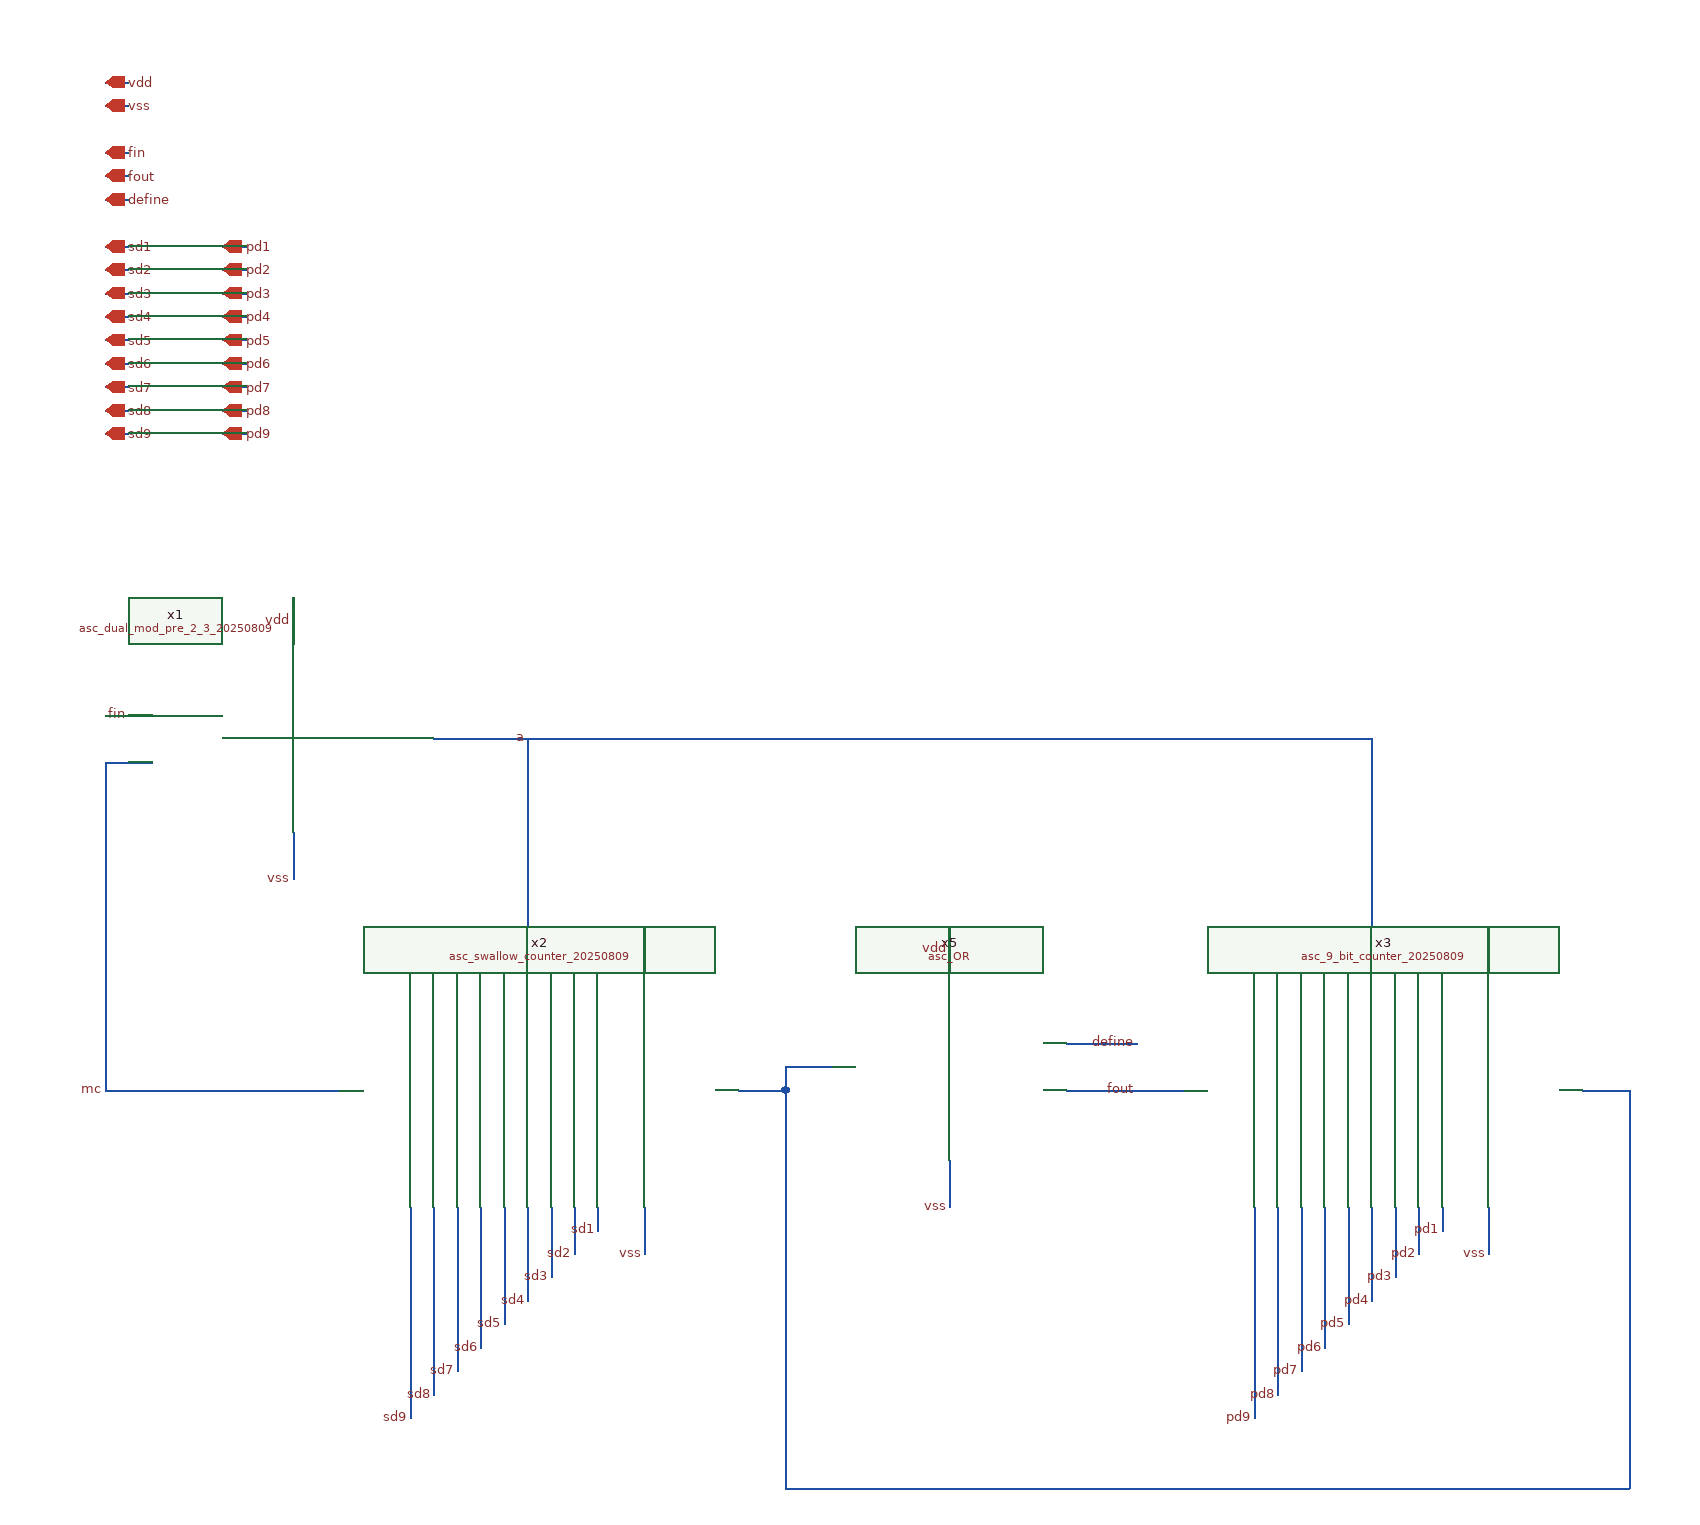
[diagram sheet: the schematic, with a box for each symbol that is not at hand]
v {xschem version=3.4.7 file_version=1.2}
G {}
K {}
V {}
S {}
E {}
N 280 -820 280 -780 {lab=vdd}
N 280 -620 280 -580 {lab=vss}
N 400 -700 540 -700 {lab=a}
N 120 -720 160 -720 {lab=fin}
N 580 -300 580 -260 {lab=vss}
N 580 -540 580 -500 {lab=vdd}
N 480 -700 480 -500 {lab=a}
N 520 -300 520 -270 {lab=sd2}
N 520 -270 520 -260 {lab=sd2}
N 500 -300 500 -260 {lab=sd3}
N 480 -300 480 -260 {lab=sd4}
N 460 -300 460 -260 {lab=sd5}
N 440 -300 440 -260 {lab=sd6}
N 420 -300 420 -260 {lab=sd7}
N 380 -300 380 -270 {lab=sd9}
N 380 -270 380 -260 {lab=sd9}
N 120 -400 320 -400 {lab=mc}
N 120 -680 120 -400 {lab=mc}
N 120 -680 160 -680 {lab=mc}
N 400 -300 400 -260 {lab=sd8}
N 380 -260 380 -160 {lab=sd9}
N 380 -160 380 -140 {lab=sd9}
N 380 -140 380 -120 {lab=sd9}
N 400 -260 400 -140 {lab=sd8}
N 420 -260 420 -160 {lab=sd7}
N 440 -260 440 -180 {lab=sd6}
N 460 -260 460 -200 {lab=sd5}
N 480 -260 480 -220 {lab=sd4}
N 500 -260 500 -240 {lab=sd3}
N 540 -300 540 -280 {lab=sd1}
N 1300 -300 1300 -260 {lab=vss}
N 1240 -300 1240 -270 {lab=pd2}
N 1240 -270 1240 -260 {lab=pd2}
N 1220 -300 1220 -260 {lab=pd3}
N 1200 -300 1200 -260 {lab=pd4}
N 1180 -300 1180 -260 {lab=pd5}
N 1160 -300 1160 -260 {lab=pd6}
N 1140 -300 1140 -260 {lab=pd7}
N 1100 -300 1100 -270 {lab=pd9}
N 1100 -270 1100 -260 {lab=pd9}
N 1120 -300 1120 -260 {lab=pd8}
N 1100 -260 1100 -160 {lab=pd9}
N 1100 -160 1100 -140 {lab=pd9}
N 1100 -140 1100 -120 {lab=pd9}
N 1120 -260 1120 -140 {lab=pd8}
N 1140 -260 1140 -160 {lab=pd7}
N 1160 -260 1160 -180 {lab=pd6}
N 1180 -260 1180 -200 {lab=pd5}
N 1200 -260 1200 -220 {lab=pd4}
N 1220 -260 1220 -240 {lab=pd3}
N 1260 -300 1260 -280 {lab=pd1b}
N 1300 -540 1300 -500 {lab=vdd}
N 700 -420 740 -420 {lab=#net1}
N 540 -700 900 -700 {lab=a}
N 1200 -700 1200 -500 {lab=a}
N 840 -540 840 -500 {lab=vdd}
N 840 -340 840 -300 {lab=vss}
N 940 -440 980 -440 {lab=define}
N 940 -400 980 -400 {lab=fout}
N 120 -1260 140 -1260 {lab=vdd}
N 120 -1240 140 -1240 {lab=vss}
N 120 -1100 140 -1100 {lab=sd2}
N 120 -1120 140 -1120 {lab=sd1}
N 120 -1080 140 -1080 {lab=sd3}
N 120 -1040 140 -1040 {lab=sd5}
N 120 -1060 140 -1060 {lab=sd4}
N 120 -1020 140 -1020 {lab=sd6}
N 120 -980 140 -980 {lab=sd8}
N 120 -1000 140 -1000 {lab=sd7}
N 120 -960 140 -960 {lab=sd9}
N 120 -1160 140 -1160 {lab=define}
N 120 -1200 140 -1200 {lab=fin}
N 120 -1180 140 -1180 {lab=fout}
N 220 -1100 240 -1100 {lab=pd2}
N 220 -1120 240 -1120 {lab=pd1}
N 220 -1080 240 -1080 {lab=pd3}
N 220 -1040 240 -1040 {lab=pd5}
N 220 -1060 240 -1060 {lab=pd4}
N 220 -1020 240 -1020 {lab=pd6}
N 220 -980 240 -980 {lab=pd8}
N 220 -1000 240 -1000 {lab=pd7}
N 220 -960 240 -960 {lab=pd9}
N 1140 -700 1200 -700 {lab=a}
N 700 -420 700 -400 {lab=#net1}
N 660 -400 700 -400 {lab=#net1}
N 980 -400 1040 -400 {lab=fout}
N 700 -400 700 -60 {lab=#net1}
N 700 -60 1420 -60 {lab=#net1}
N 1420 -400 1420 -60 {lab=#net1}
N 1380 -400 1420 -400 {lab=#net1}
N 900 -700 1140 -700 {lab=a}
N 980 -440 1000 -440 {lab=define}
C {devices/lab_wire.sym} 280 -800 0 0 {name=p1 sig_type=std_logic lab=vdd}
C {devices/lab_wire.sym} 280 -580 0 0 {name=p3 sig_type=std_logic lab=vss}
C {devices/lab_wire.sym} 580 -520 0 0 {name=p11 sig_type=std_logic lab=vdd}
C {devices/lab_wire.sym} 1000 -400 0 0 {name=p12 sig_type=std_logic lab=fout}
C {devices/lab_wire.sym} 140 -720 0 0 {name=p9 sig_type=std_logic lab=fin}
C {devices/lab_wire.sym} 120 -400 0 0 {name=p14 sig_type=std_logic lab=mc}
C {devices/lab_wire.sym} 480 -700 0 0 {name=p15 sig_type=std_logic lab=a}
C {devices/lab_wire.sym} 1300 -520 0 0 {name=p34 sig_type=std_logic lab=vdd}
C {libs/core_analog/asc_OR/asc_OR.sym} 840 -420 0 1 {name=x5}
C {devices/lab_wire.sym} 840 -520 0 0 {name=p36 sig_type=std_logic lab=vdd}
C {devices/lab_wire.sym} 840 -300 0 0 {name=p37 sig_type=std_logic lab=vss}
C {devices/lab_wire.sym} 1000 -440 0 0 {name=p41 sig_type=std_logic lab=define}
C {devices/lab_wire.sym} 580 -260 0 0 {name=p2 sig_type=std_logic lab=vss}
C {devices/lab_wire.sym} 1300 -260 0 0 {name=p4 sig_type=std_logic lab=vss}
C {devices/iopin.sym} 120 -1260 0 1 {name=p7 lab=vdd}
C {devices/iopin.sym} 120 -1240 0 1 {name=p8 lab=vss}
C {devices/iopin.sym} 120 -1100 0 1 {name=p17 lab=sd2}
C {devices/iopin.sym} 120 -1120 0 1 {name=p18 lab=sd1}
C {devices/iopin.sym} 120 -1080 0 1 {name=p19 lab=sd3}
C {devices/iopin.sym} 120 -1040 0 1 {name=p20 lab=sd5}
C {devices/iopin.sym} 120 -1060 0 1 {name=p21 lab=sd4}
C {devices/iopin.sym} 120 -1020 0 1 {name=p22 lab=sd6}
C {devices/iopin.sym} 120 -980 0 1 {name=p23 lab=sd8}
C {devices/iopin.sym} 120 -1000 0 1 {name=p24 lab=sd7}
C {devices/iopin.sym} 120 -960 0 1 {name=p25 lab=sd9}
C {devices/iopin.sym} 120 -1160 0 1 {name=p38 lab=define}
C {devices/iopin.sym} 120 -1200 0 1 {name=p10 lab=fin}
C {devices/iopin.sym} 120 -1180 0 1 {name=p13 lab=fout}
C {devices/iopin.sym} 220 -1100 0 1 {name=p16 lab=pd2}
C {devices/iopin.sym} 220 -1120 0 1 {name=p26 lab=pd1}
C {devices/iopin.sym} 220 -1080 0 1 {name=p27 lab=pd3}
C {devices/iopin.sym} 220 -1040 0 1 {name=p28 lab=pd5}
C {devices/iopin.sym} 220 -1060 0 1 {name=p29 lab=pd4}
C {devices/iopin.sym} 220 -1020 0 1 {name=p30 lab=pd6}
C {devices/iopin.sym} 220 -980 0 1 {name=p31 lab=pd8}
C {devices/iopin.sym} 220 -1000 0 1 {name=p32 lab=pd7}
C {devices/iopin.sym} 220 -960 0 1 {name=p33 lab=pd9}
C {devices/lab_wire.sym} 540 -280 0 0 {name=p113 sig_type=std_logic lab=sd1}
C {devices/lab_wire.sym} 520 -260 0 0 {name=p114 sig_type=std_logic lab=sd2}
C {devices/lab_wire.sym} 500 -240 0 0 {name=p115 sig_type=std_logic lab=sd3}
C {devices/lab_wire.sym} 480 -220 0 0 {name=p116 sig_type=std_logic lab=sd4}
C {devices/lab_wire.sym} 460 -200 0 0 {name=p117 sig_type=std_logic lab=sd5}
C {devices/lab_wire.sym} 440 -180 0 0 {name=p118 sig_type=std_logic lab=sd6}
C {devices/lab_wire.sym} 420 -160 0 0 {name=p119 sig_type=std_logic lab=sd7}
C {devices/lab_wire.sym} 400 -140 0 0 {name=p120 sig_type=std_logic lab=sd8}
C {devices/lab_wire.sym} 380 -120 0 0 {name=p121 sig_type=std_logic lab=sd9}
C {devices/lab_wire.sym} 1180 -200 0 0 {name=p122 sig_type=std_logic lab=pd5}
C {devices/lab_wire.sym} 1260 -280 0 0 {name=p123 sig_type=std_logic lab=pd1}
C {devices/lab_wire.sym} 1240 -260 0 0 {name=p124 sig_type=std_logic lab=pd2}
C {devices/lab_wire.sym} 1220 -240 0 0 {name=p125 sig_type=std_logic lab=pd3}
C {devices/lab_wire.sym} 1200 -220 0 0 {name=p126 sig_type=std_logic lab=pd4}
C {devices/lab_wire.sym} 1140 -160 0 0 {name=p127 sig_type=std_logic lab=pd7}
C {devices/lab_wire.sym} 1120 -140 0 0 {name=p128 sig_type=std_logic lab=pd8}
C {devices/lab_wire.sym} 1100 -120 0 0 {name=p129 sig_type=std_logic lab=pd9}
C {devices/lab_wire.sym} 1160 -180 0 0 {name=p130 sig_type=std_logic lab=pd6}
C {libs/core_analog/asc_swallow_counter_20250809/asc_swallow_counter_20250809.sym} 480 -400 0 0 {name=x2}
C {libs/core_analog/asc_9_bit_counter_20250809/asc_9_bit_counter_20250809.sym} 1200 -400 0 0 {name=x3}
C {libs/core_analog/asc_dual_mod_pre_2_3_20250809/asc_dual_mod_pre_2_3_20250809.sym} 280 -700 0 0 {name=x1}
